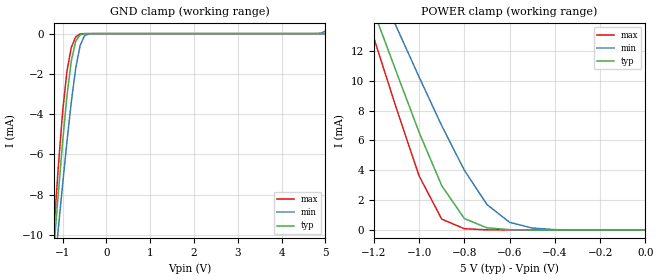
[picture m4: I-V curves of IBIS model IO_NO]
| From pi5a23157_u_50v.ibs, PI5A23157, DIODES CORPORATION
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[Model]   IO_NO
Model_type   Terminator
C_comp   2.888pF   2.851pF   2.948pF
[Voltage Range]   5   4.5   5.5
[Temperature Range]   25   -40   125
[GND Clamp Reference]   0   0   0
[POWER Clamp Reference]   5   4.5   5.5
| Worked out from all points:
|   GND clamp passes 1 mA (typ) near -0.76 V on its own axis
|   POWER clamp passes 1 mA (typ) near -0.81 V on its own axis
[GND_Clamp]
-5V       -8.922A    -8.398A    -9.402A
-1.2V     -10.73mA   -12.06mA   -9.815mA
-1.1V     -8.002mA   -9.748mA   -6.689mA
-1V       -5.402mA   -7.504mA   -3.897mA
-900mV    -3.084mA   -5.355mA   -1.856mA
-800mV    -1.348mA   -3.375mA   -678.2uA
-700mV    -375.7uA   -1.713mA   -162uA
-600mV    -59.31uA   -592.2uA   -14.43uA
-500mV    -5.325uA   -108.5uA   -563.8nA
-400mV    -316.6nA   -10.9uA    -13.88nA
4.8V      508pA      2.336uA    422.7pA
5V        766.6pA    130.5uA    480.3pA
[Power_Clamp]
-5V       97.88mA    71.82mA    120.4mA
-1.3V     18.55mA    20.11mA    17.36mA
-1.2V     14.63mA    16.91mA    12.87mA
-1.1V     10.57mA    13.6mA     8.134mA
-1V       6.542mA    10.25mA    3.625mA
-900mV    2.968mA    6.985mA    725.8uA
-800mV    765.1uA    4mA        83.69uA
-700mV    142.5uA    1.7mA      7.895uA
-600mV    19.39uA    512.9uA    574.3nA
-500mV    1.925uA    130.5uA    24.51nA
-400mV    133.8nA    21.07uA    2.543nA
0V        768.1pA    5.616nA    837pA
